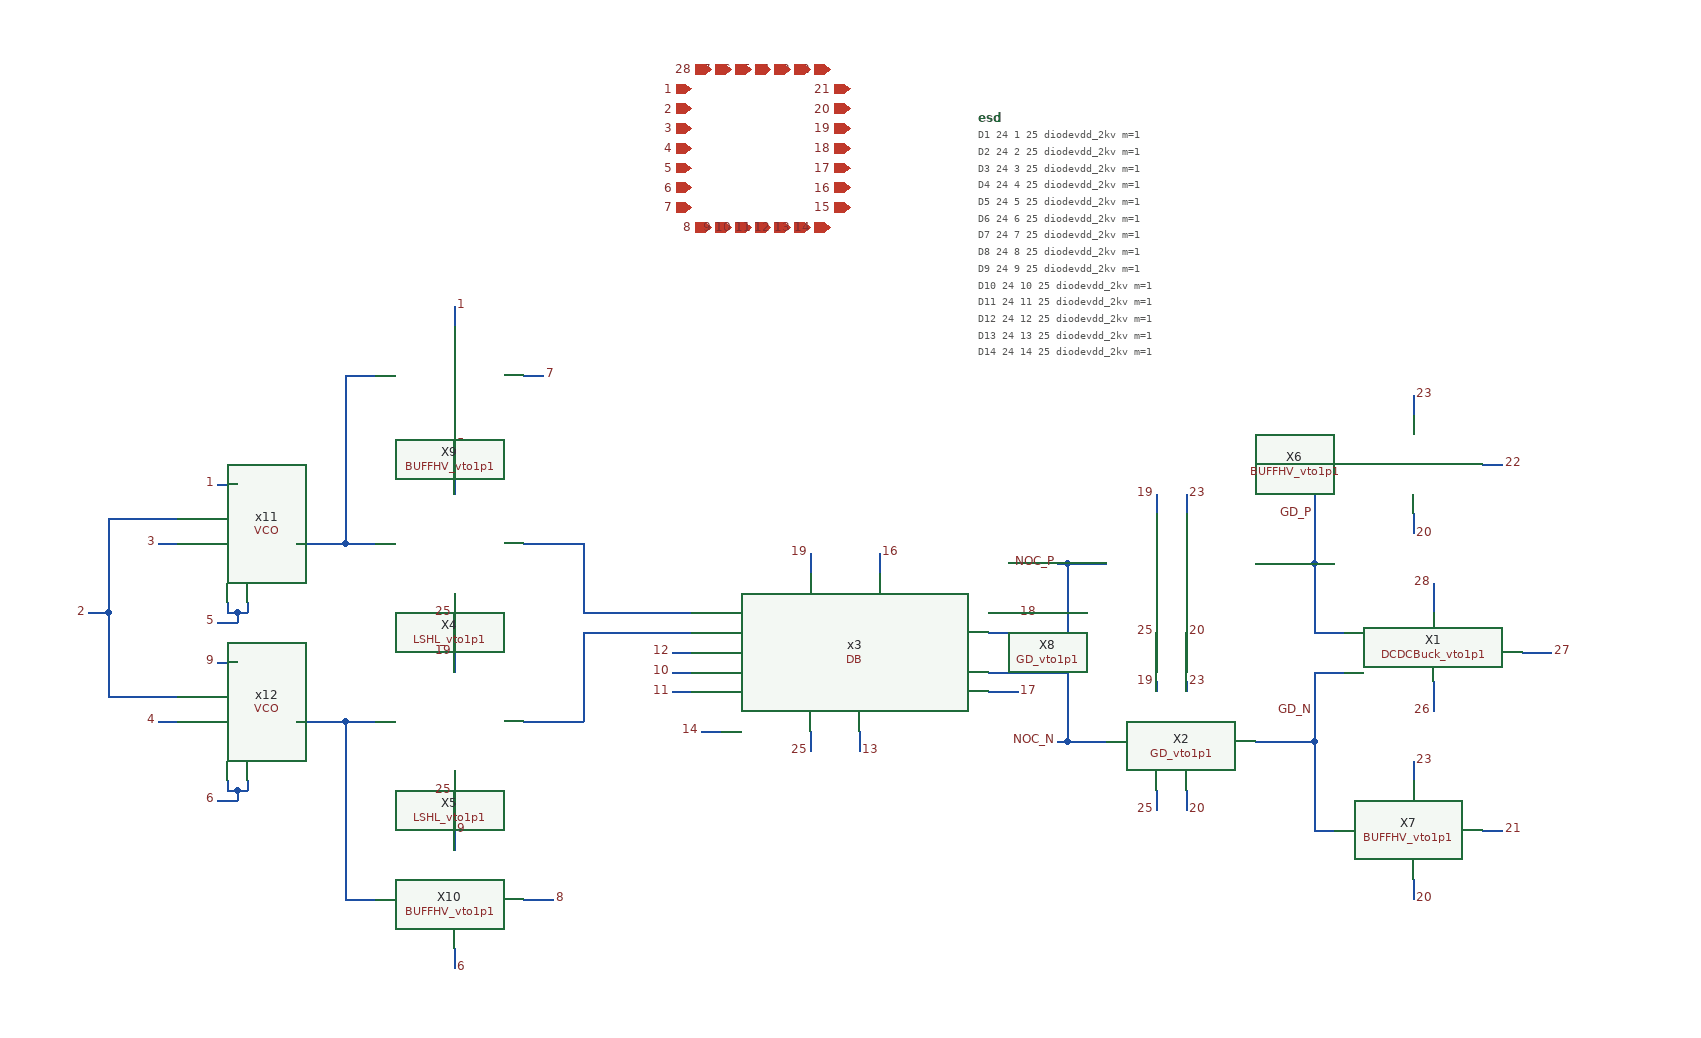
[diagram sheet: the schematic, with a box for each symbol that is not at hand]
v {xschem version=3.4.5 file_version=1.2
}
G {}
K {}
V {}
S {}
E {}
N -120 260 -120 280 {
lab=19}
N 60 340 140 340 {
lab=NOC_P}
N 60 380 140 380 {
lab=NOC_N}
N -230 440 -210 440 {
lab=14}
N 330 270 390 270 {
lab=GD_P}
N 330 450 390 450 {
lab=GD_N}
N 390 340 420 340 {
lab=GD_P}
N 390 270 390 340 {
lab=GD_P}
N 390 380 420 380 {
lab=GD_N}
N 390 380 390 450 {
lab=GD_N}
N 510 290 510 320 {
lab=28}
N 600 360 630 360 {
lab=27}
N 510 390 510 420 {
lab=26}
N 140 380 140 450 {
lab=NOC_N}
N 140 270 140 340 {
lab=NOC_P}
N 140 270 180 270 {
lab=NOC_P}
N 260 390 260 400 {
lab=23}
N 260 500 260 520 {
lab=20}
N 260 320 260 340 {
lab=20}
N 230 390 230 400 {
lab=19}
N 230 200 230 220 {
lab=19}
N 260 200 260 220 {
lab=23}
N 230 500 230 520 {
lab=25}
N -120 440 -120 460 {
lab=25}
N 230 320 230 340 {
lab=25}
N 60 400 90 400 {
lab=17}
N 60 320 90 320 {
lab=18}
N 390 170 390 270 {
lab=GD_P}
N 390 450 390 540 {
lab=GD_N}
N -50 260 -50 280 {
lab=16}
N 140 450 180 450 {
lab=NOC_N}
N 130 270 140 270 {
lab=NOC_P}
N 130 450 140 450 {
lab=NOC_N}
N -260 360 -240 360 {
lab=12}
N -260 400 -240 400 {
lab=11}
N -260 380 -240 380 {
lab=10}
N -350 320 -240 320 {
lab=#net1}
N -350 250 -350 320 {
lab=#net1}
N -410 250 -350 250 {
lab=#net1}
N -410 430 -350 430 {
lab=#net2}
N -480 180 -480 200 {
lab=19}
N -480 300 -480 320 {
lab=25}
N -480 480 -480 500 {
lab=25}
N -480 360 -480 380 {
lab=19}
N -350 340 -350 430 {
lab=#net2}
N -350 340 -240 340 {
lab=#net2}
N 560 170 580 170 {
lab=22}
N 390 170 410 170 {
lab=GD_P}
N 490 100 490 120 {
lab=23}
N 490 220 490 240 {
lab=20}
N 490 470 490 490 {
lab=23}
N 490 590 490 610 {
lab=20}
N 560 540 580 540 {
lab=21}
N 390 540 410 540 {
lab=GD_N}
N -480 10 -480 30 {
lab=1}
N -480 540 -480 560 {
lab=9}
N -480 130 -480 150 {
lab=5}
N -480 660 -480 680 {
lab=6}
N -410 80 -390 80 {
lab=7}
N -410 610 -380 610 {
lab=8}
N -590 250 -560 250 {
lab=#net3}
N -590 430 -560 430 {
lab=#net4}
N -590 430 -590 610 {
lab=#net4}
N -640 430 -590 430 {
lab=#net4}
N -590 610 -560 610 {
lab=#net4}
N -590 80 -590 250 {
lab=#net3}
N -640 250 -590 250 {
lab=#net3}
N -590 80 -560 80 {
lab=#net3}
N -70 440 -70 460 {
lab=13}
N -710 310 -710 320 {
lab=5}
N -700 320 -690 320 {
lab=5}
N -690 310 -690 320 {
lab=5}
N -710 490 -710 500 {
lab=6}
N -700 500 -690 500 {
lab=6}
N -690 490 -690 500 {
lab=6}
N -720 370 -700 370 {
lab=9}
N -720 510 -700 510 {
lab=6}
N -700 500 -700 510 {
lab=6}
N -710 500 -700 500 {
lab=6}
N -720 190 -700 190 {
lab=1}
N -720 330 -700 330 {
lab=5}
N -700 320 -700 330 {
lab=5}
N -710 320 -700 320 {
lab=5}
N -830 225 -760 225 {
lab=2}
N -830 320 -830 405 {
lab=2}
N -830 405 -760 405 {
lab=2}
N -780 250 -760 250 {
lab=3}
N -780 430 -760 430 {
lab=4}
N -850 320 -830 320 {
lab=2}
N -830 225 -830 320 {
lab=2}
C {iopin.sym} -240 -210 2 0 {name=p8 lab=1}
C {iopin.sym} -240 -190 2 0 {name=p9 lab=2}
C {iopin.sym} -240 -170 2 0 {name=p10 lab=3}
C {iopin.sym} -240 -150 2 0 {name=p11 lab=4}
C {iopin.sym} -240 -130 2 0 {name=p12 lab=5}
C {iopin.sym} -240 -110 2 0 {name=p13 lab=6}
C {iopin.sym} -240 -90 2 0 {name=p14 lab=7}
C {iopin.sym} -220 -70 1 0 {name=p15 lab=8}
C {iopin.sym} -200 -70 1 0 {name=p16 lab=9}
C {iopin.sym} -180 -70 1 0 {name=p17 lab=10}
C {iopin.sym} -160 -70 1 0 {name=p18 lab=11}
C {iopin.sym} -140 -70 1 0 {name=p19 lab=12}
C {iopin.sym} -120 -70 1 0 {name=p20 lab=13}
C {iopin.sym} -100 -70 1 0 {name=p21 lab=14}
C {iopin.sym} -80 -90 0 0 {name=p22 lab=15}
C {iopin.sym} -80 -110 0 0 {name=p23 lab=16}
C {iopin.sym} -80 -130 0 0 {name=p24 lab=17}
C {iopin.sym} -80 -150 0 0 {name=p25 lab=18}
C {iopin.sym} -80 -170 0 0 {name=p26 lab=19}
C {iopin.sym} -80 -190 0 0 {name=p27 lab=20}
C {iopin.sym} -80 -210 0 0 {name=p28 lab=21}
C {iopin.sym} -100 -230 3 0 {name=p29 lab=22}
C {iopin.sym} -120 -230 3 0 {name=p30 lab=23}
C {iopin.sym} -140 -230 3 0 {name=p31 lab=24}
C {iopin.sym} -160 -230 3 0 {name=p32 lab=25}
C {iopin.sym} -180 -230 3 0 {name=p33 lab=26}
C {iopin.sym} -200 -230 3 0 {name=p34 lab=27}
C {iopin.sym} -220 -230 3 0 {name=p35 lab=28}
C {lab_pin.sym} -120 260 1 0 {name=p3 sig_type=std_logic lab=19}
C {lab_pin.sym} -230 440 0 0 {name=p39 sig_type=std_logic lab=14}
C {lab_pin.sym} 580 170 0 1 {name=p2 sig_type=std_logic lab=22}
C {lab_pin.sym} 580 540 0 1 {name=p4 sig_type=std_logic lab=21}
C {lab_pin.sym} 260 200 2 0 {name=p6 sig_type=std_logic lab=23}
C {lab_pin.sym} 260 390 2 0 {name=p7 sig_type=std_logic lab=23
}
C {lab_pin.sym} 510 290 0 0 {name=p36 sig_type=std_logic lab=28}
C {lab_pin.sym} 510 420 0 0 {name=p37 sig_type=std_logic lab=26}
C {lab_pin.sym} 630 360 2 0 {name=p41 sig_type=std_logic lab=27}
C {lab_pin.sym} 230 390 0 0 {name=p44 sig_type=std_logic lab=19}
C {lab_pin.sym} 230 200 0 0 {name=p45 sig_type=std_logic lab=19}
C {lab_pin.sym} 90 320 0 1 {name=p46 sig_type=std_logic lab=18
}
C {lab_pin.sym} 90 400 0 1 {name=p47 sig_type=std_logic lab=17
}
C {lab_pin.sym} 230 340 2 1 {name=p5 sig_type=std_logic lab=25
}
C {lab_pin.sym} 230 520 2 1 {name=p42 sig_type=std_logic lab=25
}
C {lab_pin.sym} -120 460 2 1 {name=p40 sig_type=std_logic lab=25
}
C {lab_pin.sym} 260 520 0 1 {name=p1 sig_type=std_logic lab=20
}
C {lab_pin.sym} 260 340 0 1 {name=p43 sig_type=std_logic lab=20
}
C {lab_pin.sym} -50 260 0 1 {name=p53 sig_type=std_logic lab=16
}
C {lab_pin.sym} 390 220 2 1 {name=p63 sig_type=std_logic lab=GD_P}
C {lab_pin.sym} 390 420 2 1 {name=p64 sig_type=std_logic lab=GD_N}
C {../GD/GD_vto1p1.sym} 210 310 0 0 {name=X8}
C {../DCDCBuck/DCDCBuck_vto1p1.sym} 520 380 0 0 {name=X1}
C {../GD/GD_vto1p1.sym} 210 490 0 0 {name=X2}
C {lab_pin.sym} 130 270 2 1 {name=p50 sig_type=std_logic lab=NOC_P}
C {lab_pin.sym} 130 450 2 1 {name=p51 sig_type=std_logic lab=NOC_N}
C {../Digital_Block/DB.sym} -90 360 0 0 {name=x3}
C {lab_pin.sym} -260 360 0 0 {name=p52 sig_type=std_logic lab=12}
C {lab_pin.sym} -260 400 0 0 {name=p54 sig_type=std_logic lab=11}
C {lab_pin.sym} -260 380 0 0 {name=p55 sig_type=std_logic lab=10}
C {../LSHL/LSHL_vto1p1.sym} -530 290 0 0 {name=X4}
C {../LSHL/LSHL_vto1p1.sym} -530 470 0 0 {name=X5}
C {lab_pin.sym} -480 180 0 0 {name=p48 sig_type=std_logic lab=19}
C {lab_pin.sym} -480 320 2 1 {name=p49 sig_type=std_logic lab=25
}
C {lab_pin.sym} -480 500 2 1 {name=p56 sig_type=std_logic lab=25
}
C {lab_pin.sym} -480 360 0 0 {name=p57 sig_type=std_logic lab=19}
C {../BUFFHV/BUFFHV_vto1p1.sym} 440 210 0 0 {name=X6}
C {lab_pin.sym} 490 100 2 0 {name=p58 sig_type=std_logic lab=23}
C {lab_pin.sym} 490 240 0 1 {name=p59 sig_type=std_logic lab=20
}
C {../BUFFHV/BUFFHV_vto1p1.sym} 440 580 0 0 {name=X7}
C {lab_pin.sym} 490 470 2 0 {name=p60 sig_type=std_logic lab=23}
C {lab_pin.sym} 490 610 0 1 {name=p61 sig_type=std_logic lab=20
}
C {lab_pin.sym} -480 10 2 0 {name=p62 sig_type=std_logic lab=1}
C {lab_pin.sym} -480 540 2 0 {name=p65 sig_type=std_logic lab=9}
C {lab_pin.sym} -480 150 2 0 {name=p66 sig_type=std_logic lab=5}
C {lab_pin.sym} -480 680 2 0 {name=p67 sig_type=std_logic lab=6}
C {lab_pin.sym} -390 80 2 0 {name=p68 sig_type=std_logic lab=7}
C {lab_pin.sym} -380 610 2 0 {name=p69 sig_type=std_logic lab=8}
C {lab_pin.sym} -70 460 2 0 {name=p72 sig_type=std_logic lab=13
}
C {code.sym} 50 -180 0 0 {name=esd only_toplevel=false spice_ignore=false value="
D1 24 1 25 diodevdd_2kv m=1
D2 24 2 25 diodevdd_2kv m=1
D3 24 3 25 diodevdd_2kv m=1
D4 24 4 25 diodevdd_2kv m=1
D5 24 5 25 diodevdd_2kv m=1
D6 24 6 25 diodevdd_2kv m=1
D7 24 7 25 diodevdd_2kv m=1
D8 24 8 25 diodevdd_2kv m=1
D9 24 9 25 diodevdd_2kv m=1
D10 24 10 25 diodevdd_2kv m=1
D11 24 11 25 diodevdd_2kv m=1
D12 24 12 25 diodevdd_2kv m=1
D13 24 13 25 diodevdd_2kv m=1
D14 24 14 25 diodevdd_2kv m=1
D15 24 25 25 diodevdd_2kv m=1
D16 24 16 25 diodevdd_2kv m=1
D17 24 17 25 diodevdd_2kv m=1
D18 24 18 25 diodevdd_2kv m=1
D19 24 19 25 diodevdd_2kv m=1
D20 24 20 25 diodevdd_2kv m=1
D21 24 21 25 diodevdd_2kv m=1
D22 24 22 25 diodevdd_2kv m=1
D23 24 23 25 diodevdd_2kv m=1
D24 24 24 25 diodevdd_2kv m=1
D25 24 25 25 diodevdd_2kv m=1
D26 24 26 25 diodevdd_2kv m=1
D27 24 27 25 diodevdd_2kv m=1
D28 24 28 25 diodevdd_2kv m=1

D29 24 1 25 diodevss_2kv m=1
D30 24 2 25 diodevss_2kv m=1
D31 24 3 25 diodevss_2kv m=1
D32 24 4 25 diodevss_2kv m=1
D33 24 5 25 diodevss_2kv m=1
D34 24 6 25 diodevss_2kv m=1
D35 24 7 25 diodevss_2kv m=1
D36 24 8 25 diodevss_2kv m=1
D37 24 9 25 diodevss_2kv m=1
D38 24 10 25 diodevss_2kv m=1
D39 24 11 25 diodevss_2kv m=1
D40 24 12 25 diodevss_2kv m=1
D41 24 13 25 diodevss_2kv m=1
D42 24 14 25 diodevss_2kv m=1
D43 24 25 25 diodevss_2kv m=1
D44 24 16 25 diodevss_2kv m=1
D45 24 17 25 diodevss_2kv m=1
D46 24 18 25 diodevss_2kv m=1
D47 24 19 25 diodevss_2kv m=1
D48 24 20 25 diodevss_2kv m=1
D49 24 21 25 diodevss_2kv m=1
D50 24 22 25 diodevss_2kv m=1
D51 24 23 25 diodevss_2kv m=1
D52 24 24 25 diodevss_2kv m=1
D53 24 25 25 diodevss_2kv m=1
D54 24 26 25 diodevss_2kv m=1
D55 24 27 25 diodevss_2kv m=1
D56 24 28 25 diodevss_2kv m=1
"}
C {/workspaces/usm-vlsi-tools/shared_xserver/TORepo_IHPNov2024_TDBuck/design_data/xschem/VCO/VCO.sym} -700 250 0 0 {name=x11}
C {/workspaces/usm-vlsi-tools/shared_xserver/TORepo_IHPNov2024_TDBuck/design_data/xschem/VCO/VCO.sym} -700 430 0 0 {name=x12}
C {lab_pin.sym} -720 370 0 0 {name=p38 sig_type=std_logic lab=9}
C {lab_pin.sym} -720 510 0 0 {name=p70 sig_type=std_logic lab=6}
C {lab_pin.sym} -720 190 0 0 {name=p71 sig_type=std_logic lab=1}
C {lab_pin.sym} -720 330 0 0 {name=p73 sig_type=std_logic lab=5}
C {lab_pin.sym} -780 250 0 0 {name=p74 sig_type=std_logic lab=3}
C {lab_pin.sym} -780 430 0 0 {name=p75 sig_type=std_logic lab=4}
C {lab_pin.sym} -850 320 0 0 {name=p76 sig_type=std_logic lab=2}
C {../BUFFHV/BUFFHV_vto1p1.sym} -530 120 0 0 {name=X9}
C {../BUFFHV/BUFFHV_vto1p1.sym} -530 650 0 0 {name=X10}
